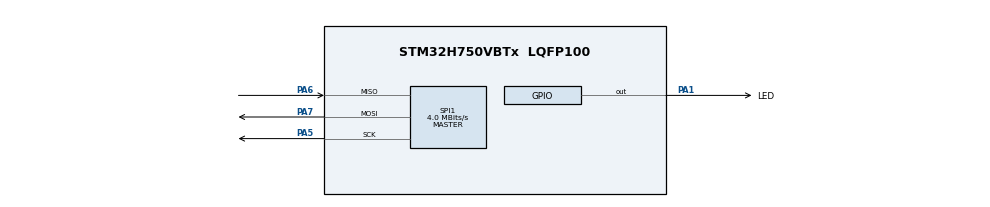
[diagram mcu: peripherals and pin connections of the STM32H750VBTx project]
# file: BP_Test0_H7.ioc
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CORTEX_M7.MPU_Control=__NULL
Mcu.Family=STM32H7
Mcu.Name=STM32H750VBTx
Mcu.Package=LQFP100
NVIC.PriorityGroup=NVIC_PRIORITYGROUP_4
PA1.GPIO_Label=LED
PA1.Signal=GPIO_Output
PA13\ (JTMS/SWDIO).Mode=Trace_Synchro_4bits_SW
PA13\ (JTMS/SWDIO).Signal=DEBUG_JTMS-SWDIO
PA14\ (JTCK/SWCLK).Mode=Trace_Synchro_4bits_SW
PA14\ (JTCK/SWCLK).Signal=DEBUG_JTCK-SWCLK
PA5.Mode=Full_Duplex_Master
PA5.Signal=SPI1_SCK
PA6.Mode=Full_Duplex_Master
PA6.Signal=SPI1_MISO
PA7.Mode=Full_Duplex_Master
PA7.Signal=SPI1_MOSI
PE2.Mode=Trace_Synchro_4bits_SW
PE2.Signal=DEBUG_TRACECLK
PE3.Mode=Trace_Synchro_4bits_SW
PE3.Signal=DEBUG_TRACED0
PE4.Mode=Trace_Synchro_4bits_SW
PE4.Signal=DEBUG_TRACED1
PE5.Mode=Trace_Synchro_4bits_SW
PE5.Signal=DEBUG_TRACED2
PE6.Mode=Trace_Synchro_4bits_SW
PE6.Signal=DEBUG_TRACED3
ProjectManager.HeapSize=0x200
ProjectManager.StackSize=0x400
ProjectManager.TargetToolchain=STM32CubeIDE
RCC.ADCFreq_Value=2000000
RCC.APB1Freq_Value=1000000
RCC.APB2Freq_Value=1000000
RCC.APB3Freq_Value=1000000
RCC.APB4Freq_Value=1000000
RCC.CortexFreq_Value=1000000
RCC.D1CPRE=RCC_SYSCLK_DIV2
RCC.DIVM1=2
RCC.DIVM2=2
RCC.DIVM3=2
RCC.DIVN1=38
RCC.DIVN2=4
RCC.DIVN3=4
RCC.DIVP1=76
RCC.DIVP2=8
RCC.DIVP3=8
RCC.DIVQ1=76
RCC.DIVR1=76
RCC.HCLKFreq_Value=1000000
RCC.HSE_VALUE=25000000
RCC.HSICalibrationValue=64
RCC.HSIDiv=RCC_PLLSAIDIVR_8
RCC.PLLFRACN=0
RCC.SPI123CLockSelection=RCC_SPI123CLKSOURCE_CLKP
RCC.SYSCLKFreq_VALUE=2000000
RCC.SYSCLKSource=RCC_SYSCLKSOURCE_PLLCLK
RCC.USBFreq_Value=2000000
SPI1.CalculateBaudRate=4.0 MBits/s
SPI1.DataSize=SPI_DATASIZE_8BIT
SPI1.Direction=SPI_DIRECTION_2LINES
SPI1.Mode=SPI_MODE_MASTER
SPI1.VirtualType=VM_MASTER
VP_MEMORYMAP_VS_MEMORYMAP.Mode=CurAppReg
board=custom

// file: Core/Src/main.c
/* USER CODE BEGIN Header */
/**
  ******************************************************************************
  * @file           : main.c
  * @brief          : Main program body
  ******************************************************************************
  * @attention
  *
  * Copyright (c) 2026 STMicroelectronics.
  * All rights reserved.
  *
  * This software is licensed under terms that can be found in the LICENSE file
  * in the root directory of this software component.
  * If no LICENSE file comes with this software, it is provided AS-IS.
  *
  ******************************************************************************
  */
/* USER CODE END Header */
#include "main.h"

/* USER CODE BEGIN Includes */
#include "ETMv4.h"
/* USER CODE END Includes */

/* USER CODE BEGIN PD */
// CoreSight Lock Access Key
/* USER CODE END PD */

SPI_HandleTypeDef hspi1;

void SystemClock_Config(void);
void PeriphCommonClock_Config(void);
static void MX_GPIO_Init(void);
static void MX_SPI1_Init(void);
/* USER CODE BEGIN PFP */
void Configure_ETM_Trace(void);
void StartPoint(void);
void StopPoint(void);

/* USER CODE END PFP */

int main(void)
{

  /* MCU Configuration--------------------------------------------------------*/

  /* Reset of all peripherals, Initializes the Flash interface and the Systick. */
  HAL_Init();

  /* Configure the system clock */
  SystemClock_Config();

  /* Configure the peripherals common clocks */
  PeriphCommonClock_Config();

  /* Initialize all configured peripherals */
  MX_GPIO_Init();
  MX_SPI1_Init();
  /* USER CODE BEGIN 2 */
  // Enable TRACECK in DBGMCU_CR
  // Note: DBGMCU base address is usually 0x5C001000 on STM32H7
  uint8_t temp[] = "HelloMom";
  uint8_t RecBuff[9];
  Parallel_Trace_configure();
  //GPIO_TraceSWO_Init();
  //System_Trace_Pipeline_Init(2);3
  //TraceGPIO_Configure();

  /* USER CODE END 2 */

  /* Infinite loop */
  /* USER CODE BEGIN WHILE */
  StartPoint();

  while (1)
  {
	  HAL_SPI_Transmit(&hspi1, temp,  sizeof(temp), 100);
	  HAL_Delay(500);
	  HAL_GPIO_TogglePin(LED_GPIO_Port,LED_Pin);
	  //HAL_I2C_Master_Transmit(&hi2c1, 0x01,temp, sizeof(temp), 100);
	  //HAL_I2C_Slave_Transmit(&hi2c1,temp, sizeof(temp), 100);

    /* USER CODE END WHILE */
  StopPoint();

  }
}

void SystemClock_Config(void)
{
  RCC_OscInitTypeDef RCC_OscInitStruct = {0};
  RCC_ClkInitTypeDef RCC_ClkInitStruct = {0};

  /** Supply configuration update enable
  */
  HAL_PWREx_ConfigSupply(PWR_LDO_SUPPLY);

  /** Configure the main internal regulator output voltage
  */
  __HAL_PWR_VOLTAGESCALING_CONFIG(PWR_REGULATOR_VOLTAGE_SCALE3);

  while(!__HAL_PWR_GET_FLAG(PWR_FLAG_VOSRDY)) {}

  /** Initializes the RCC Oscillators according to the specified parameters
  * in the RCC_OscInitTypeDef structure.
  */
  RCC_OscInitStruct.OscillatorType = RCC_OSCILLATORTYPE_HSI;
  RCC_OscInitStruct.HSIState = RCC_HSI_DIV8;
  RCC_OscInitStruct.HSICalibrationValue = RCC_HSICALIBRATION_DEFAULT;
  RCC_OscInitStruct.PLL.PLLState = RCC_PLL_ON;
  RCC_OscInitStruct.PLL.PLLSource = RCC_PLLSOURCE_HSI;
  RCC_OscInitStruct.PLL.PLLM = 2;
  RCC_OscInitStruct.PLL.PLLN = 38;
  RCC_OscInitStruct.PLL.PLLP = 76;
  RCC_OscInitStruct.PLL.PLLQ = 76;
  RCC_OscInitStruct.PLL.PLLR = 76;
  RCC_OscInitStruct.PLL.PLLRGE = RCC_PLL1VCIRANGE_2;
  RCC_OscInitStruct.PLL.PLLVCOSEL = RCC_PLL1VCOMEDIUM;
  RCC_OscInitStruct.PLL.PLLFRACN = 0;
  if (HAL_RCC_OscConfig(&RCC_OscInitStruct) != HAL_OK)
  {
    Error_Handler();
  }

  /** Initializes the CPU, AHB and APB buses clocks
  */
  RCC_ClkInitStruct.ClockType = RCC_CLOCKTYPE_HCLK|RCC_CLOCKTYPE_SYSCLK
                              |RCC_CLOCKTYPE_PCLK1|RCC_CLOCKTYPE_PCLK2
                              |RCC_CLOCKTYPE_D3PCLK1|RCC_CLOCKTYPE_D1PCLK1;
  RCC_ClkInitStruct.SYSCLKSource = RCC_SYSCLKSOURCE_PLLCLK;
  RCC_ClkInitStruct.SYSCLKDivider = RCC_SYSCLK_DIV2;
  RCC_ClkInitStruct.AHBCLKDivider = RCC_HCLK_DIV1;
  RCC_ClkInitStruct.APB3CLKDivider = RCC_APB3_DIV1;
  RCC_ClkInitStruct.APB1CLKDivider = RCC_APB1_DIV1;
  RCC_ClkInitStruct.APB2CLKDivider = RCC_APB2_DIV1;
  RCC_ClkInitStruct.APB4CLKDivider = RCC_APB4_DIV1;

  if (HAL_RCC_ClockConfig(&RCC_ClkInitStruct, FLASH_LATENCY_0) != HAL_OK)
  {
    Error_Handler();
  }
}

void PeriphCommonClock_Config(void)
{
  RCC_PeriphCLKInitTypeDef PeriphClkInitStruct = {0};

  /** Initializes the peripherals clock
  */
  PeriphClkInitStruct.PeriphClockSelection = RCC_PERIPHCLK_CKPER;
  PeriphClkInitStruct.CkperClockSelection = RCC_CLKPSOURCE_HSI;
  if (HAL_RCCEx_PeriphCLKConfig(&PeriphClkInitStruct) != HAL_OK)
  {
    Error_Handler();
  }
}

static void MX_SPI1_Init(void)
{

  /* SPI1 parameter configuration*/
  hspi1.Instance = SPI1;
  hspi1.Init.Mode = SPI_MODE_MASTER;
  hspi1.Init.Direction = SPI_DIRECTION_2LINES;
  hspi1.Init.DataSize = SPI_DATASIZE_8BIT;
  hspi1.Init.CLKPolarity = SPI_POLARITY_LOW;
  hspi1.Init.CLKPhase = SPI_PHASE_1EDGE;
  hspi1.Init.NSS = SPI_NSS_SOFT;
  hspi1.Init.BaudRatePrescaler = SPI_BAUDRATEPRESCALER_2;
  hspi1.Init.FirstBit = SPI_FIRSTBIT_MSB;
  hspi1.Init.TIMode = SPI_TIMODE_DISABLE;
  hspi1.Init.CRCCalculation = SPI_CRCCALCULATION_DISABLE;
  hspi1.Init.CRCPolynomial = 0x0;
  hspi1.Init.NSSPMode = SPI_NSS_PULSE_ENABLE;
  hspi1.Init.NSSPolarity = SPI_NSS_POLARITY_LOW;
  hspi1.Init.FifoThreshold = SPI_FIFO_THRESHOLD_01DATA;
  hspi1.Init.TxCRCInitializationPattern = SPI_CRC_INITIALIZATION_ALL_ZERO_PATTERN;
  hspi1.Init.RxCRCInitializationPattern = SPI_CRC_INITIALIZATION_ALL_ZERO_PATTERN;
  hspi1.Init.MasterSSIdleness = SPI_MASTER_SS_IDLENESS_00CYCLE;
  hspi1.Init.MasterInterDataIdleness = SPI_MASTER_INTERDATA_IDLENESS_00CYCLE;
  hspi1.Init.MasterReceiverAutoSusp = SPI_MASTER_RX_AUTOSUSP_DISABLE;
  hspi1.Init.MasterKeepIOState = SPI_MASTER_KEEP_IO_STATE_DISABLE;
  hspi1.Init.IOSwap = SPI_IO_SWAP_DISABLE;
  if (HAL_SPI_Init(&hspi1) != HAL_OK)
  {
    Error_Handler();
  }

}

static void MX_GPIO_Init(void)
{
  GPIO_InitTypeDef GPIO_InitStruct = {0};

  /* GPIO Ports Clock Enable */
  __HAL_RCC_GPIOE_CLK_ENABLE();
  __HAL_RCC_GPIOA_CLK_ENABLE();

  /*Configure GPIO pin Output Level */
  HAL_GPIO_WritePin(LED_GPIO_Port, LED_Pin, GPIO_PIN_RESET);

  /*Configure GPIO pin : LED_Pin */
  GPIO_InitStruct.Pin = LED_Pin;
  GPIO_InitStruct.Mode = GPIO_MODE_OUTPUT_PP;
  GPIO_InitStruct.Pull = GPIO_NOPULL;
  GPIO_InitStruct.Speed = GPIO_SPEED_FREQ_LOW;
  HAL_GPIO_Init(LED_GPIO_Port, &GPIO_InitStruct);

}

/* USER CODE BEGIN 4 */

void GPIO_TraceSWO_Init(void)
{
    GPIO_InitTypeDef GPIO_InitStruct = {0};

    /* Enable GPIOB Clock */
    __HAL_RCC_GPIOB_CLK_ENABLE();

    /* Configure PB3 as JTDO/TRACE_SWO */
    GPIO_InitStruct.Pin       = GPIO_PIN_3;
    GPIO_InitStruct.Mode      = GPIO_MODE_AF_PP;       // Alternate Function Push-Pull
    GPIO_InitStruct.Pull      = GPIO_NOPULL;           // No Pull-up or Pull-down
    GPIO_InitStruct.Speed     = GPIO_SPEED_FREQ_VERY_HIGH; // Crucial for high baud rates
    GPIO_InitStruct.Alternate = GPIO_AF0_MCO;          // AF0 (System/Debug mapping)

    HAL_GPIO_Init(GPIOB, &GPIO_InitStruct);
}
/* USER CODE END 4 */

void Error_Handler(void)
{
  __disable_irq();
  while (1)
  {
  }
}
